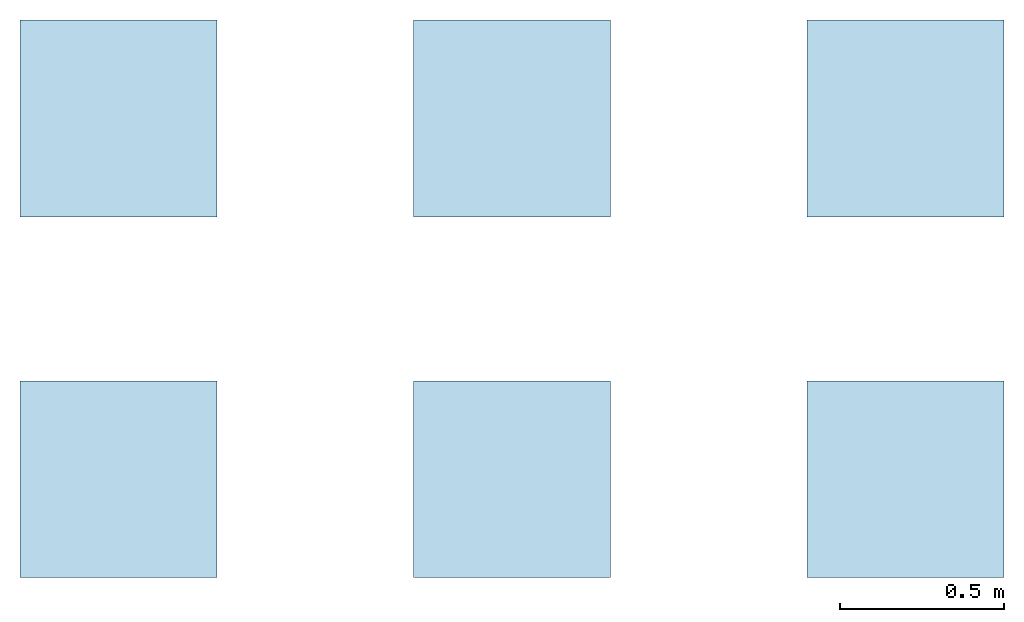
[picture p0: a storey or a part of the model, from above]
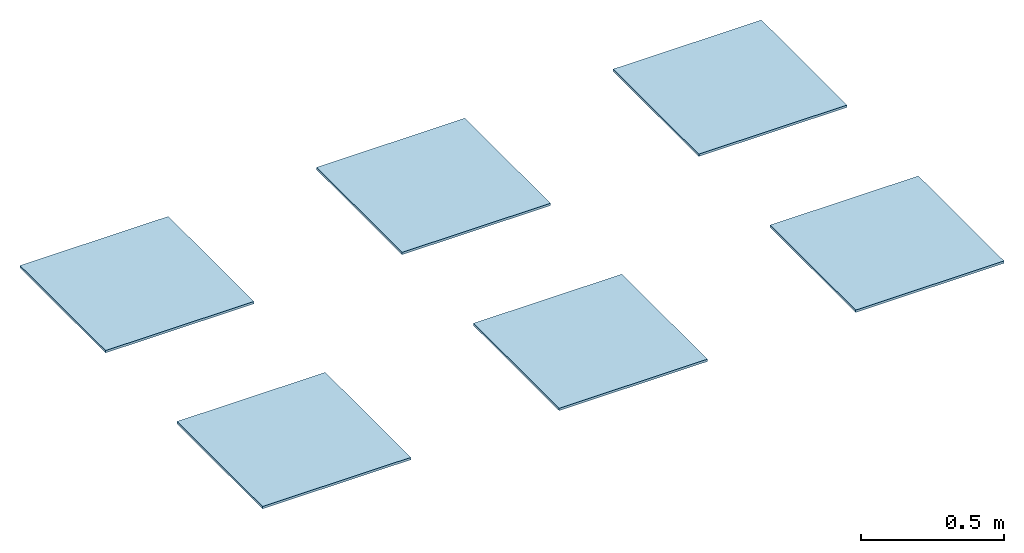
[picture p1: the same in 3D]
Properties of the parts of a building model (IFC2X3)

# File
Description: ViewDefinition [CoordinationView_V2.0]
File name: Número de proyecto
Time: 2017-10-19T11:49:41
Written by: The EXPRESS Data Manager Version 5.02.0100.07 : 28 Aug 2013
Made in: 20160225_1515(x64) - Exporter 17.0.416.0 - Alternate UI 17.12.14.0
Comment: STEP Physical File produced by: The EXPRESS Data Manager Version 5.02.0100.07 : 28 Aug 2013 * Module: EDMstepFileFactory/EDMstandAlone * Creation date: Thu Oct 19 11:49:41 2017 * Host: REVIT * Database: C:\Users\corte\AppData\Local\Temp\{BD6F1904-84B4-4D9F-9326-C3FF22E80287}\ifc * Database version: 5507 * Database creation date: Thu Oct 19 11:49:39 2017 * Schema: IFC2X3 * Model: DataRepository.ifc * Model creation date: Thu Oct 19 11:49:39 2017 * Header model: DataRepository.ifc_HeaderModel * Header model creation date: Thu Oct 19 11:49:39 2017 * EDMuser: sdai-user * EDMgroup: sdai-group * License ID and type: 5605 : Permanent license. Expiry date: * EDMstepFileFactory options: 020000

# IfcProject, Número de proyecto
LongName: Nombre de proyecto; Phase: Estado de proyecto

# IfcSite, Default
RefLatitude: 40, 25, 0, 86975; RefLongitude: -3, -42, -1, -243858; RefElevation: 0 m

# IfcBuilding
Pset_BuildingCommon - NumberOfStoreys: 2

# IfcBuildingStorey (2)
Name | LongName | Elevation (m)
LAVERTON FLOOR TILES | LAVERTON FLOOR TILES | 0
Nivel 2 | Nivel 2 | 3

# IfcSlab: Suelo:VIVES LAVERTON ARENA 60x60, Suelo:VIVES LAVERTON ARENA 60x60:189750
In: LAVERTON FLOOR TILES
PredefinedType: FLOOR; Material: VIVES LAVERTON ARENA 60x60 0.01 m
Pset_SlabCommon - Reference: VIVES LAVERTON ARENA 60x60; IsExternal: no; LoadBearing: yes; ThermalTransmittance: 150 kg/K/s3; PitchAngle: 0 deg
Pset_ManufacturerTypeInformation - Manufacturer: VIVES Azulejos y Gres S.A.

# IfcSlab: Suelo:VIVES LAVERTON BEIGE 60x60, Suelo:VIVES LAVERTON BEIGE 60x60:210667
In: LAVERTON FLOOR TILES
PredefinedType: FLOOR; Material: VIVES LAVERTON BEIGE 60x60 0.01 m
Pset_SlabCommon - IsExternal: no; LoadBearing: yes; PitchAngle: 0 deg; Reference: VIVES LAVERTON BEIGE 60x60; ThermalTransmittance: 150 kg/K/s3
Pset_ManufacturerTypeInformation - Manufacturer: VIVES Azulejos y Gres S.A.

# IfcSlab: Suelo:VIVES LAVERTON GRAFITO 60x60, Suelo:VIVES LAVERTON GRAFITO 60x60:210683
In: LAVERTON FLOOR TILES
PredefinedType: FLOOR; Material: VIVES LAVERTON GRAFITO 60x60 0.01 m
Pset_SlabCommon - IsExternal: no; LoadBearing: yes; PitchAngle: 0 deg; Reference: VIVES LAVERTON GRAFITO 60x60; ThermalTransmittance: 150 kg/K/s3
Pset_ManufacturerTypeInformation - Manufacturer: VIVES Azulejos y Gres S.A.

# IfcSlab: Suelo:VIVES LAVERTON GRIS 60x60, Suelo:VIVES LAVERTON GRIS 60x60:210675
In: LAVERTON FLOOR TILES
PredefinedType: FLOOR; Material: VIVES LAVERTON GRIS 60x60 0.01 m
Pset_SlabCommon - IsExternal: no; LoadBearing: yes; PitchAngle: 0 deg; Reference: VIVES LAVERTON GRIS 60x60; ThermalTransmittance: 150 kg/K/s3
Pset_ManufacturerTypeInformation - Manufacturer: VIVES Azulejos y Gres S.A.

# IfcSlab: Suelo:VIVES LAVERTON NATURAL 60x60, Suelo:VIVES LAVERTON NATURAL 60x60:210591
In: LAVERTON FLOOR TILES
PredefinedType: FLOOR; Material: VIVES LAVERTON NATURAL 60x60 0.01 m
Pset_SlabCommon - IsExternal: no; LoadBearing: yes; PitchAngle: 0 deg; Reference: VIVES LAVERTON NATURAL 60x60; ThermalTransmittance: 150 kg/K/s3
Pset_ManufacturerTypeInformation - Manufacturer: VIVES Azulejos y Gres S.A.

# IfcSlab: Suelo:VIVES LAVERTON NIEVE 60x60, Suelo:VIVES LAVERTON NIEVE 60x60:210450
In: LAVERTON FLOOR TILES
PredefinedType: FLOOR; Material: VIVES LAVERTON NIEVE 60x60 0.01 m
Pset_SlabCommon - IsExternal: no; LoadBearing: yes; PitchAngle: 0 deg; Reference: VIVES LAVERTON NIEVE 60x60; ThermalTransmittance: 150 kg/K/s3
Pset_ManufacturerTypeInformation - Manufacturer: VIVES Azulejos y Gres S.A.

# IfcWallStandardCase: Muro básico:VIVES LAVERTON ARENA 60x60, Muro básico:VIVES LAVERTON ARENA 60x60:204926
In: Nivel 2
Type - PredefinedType: STANDARD; Material: VIVES LAVERTON ARENA 60x60 0.01 m
Pset_WallCommon - Reference: VIVES LAVERTON ARENA 60x60; IsExternal: no; LoadBearing: no; ExtendToStructure: no; ThermalTransmittance: 150 kg/K/s3
Pset_ManufacturerTypeInformation - Manufacturer: VIVES Azulejos y Gres S.A.

# IfcWallStandardCase: Muro básico:VIVES LAVERTON BEIGE 60x60, Muro básico:VIVES LAVERTON BEIGE 60x60:211145
In: Nivel 2
Type - PredefinedType: STANDARD; Material: VIVES LAVERTON BEIGE 60x60 0.01 m
Pset_WallCommon - IsExternal: no; LoadBearing: no; ExtendToStructure: no; Reference: VIVES LAVERTON BEIGE 60x60; ThermalTransmittance: 150 kg/K/s3
Pset_ManufacturerTypeInformation - Manufacturer: VIVES Azulejos y Gres S.A.

# IfcWallStandardCase: Muro básico:VIVES LAVERTON GRAFITO 60x60, Muro básico:VIVES LAVERTON GRAFITO 60x60:211177
In: Nivel 2
Type - PredefinedType: STANDARD; Material: VIVES LAVERTON GRAFITO 60x60 0.01 m
Pset_WallCommon - IsExternal: no; LoadBearing: no; ExtendToStructure: no; Reference: VIVES LAVERTON GRAFITO 60x60; ThermalTransmittance: 150 kg/K/s3
Pset_ManufacturerTypeInformation - Manufacturer: VIVES Azulejos y Gres S.A.

# IfcWallStandardCase: Muro básico:VIVES LAVERTON GRIS 60x60, Muro básico:VIVES LAVERTON GRIS 60x60:211161
In: Nivel 2
Type - PredefinedType: STANDARD; Material: VIVES LAVERTON GRIS 60x60 0.01 m
Pset_WallCommon - IsExternal: no; LoadBearing: no; ExtendToStructure: no; Reference: VIVES LAVERTON GRIS 60x60; ThermalTransmittance: 150 kg/K/s3
Pset_ManufacturerTypeInformation - Manufacturer: VIVES Azulejos y Gres S.A.

# IfcWallStandardCase: Muro básico:VIVES LAVERTON NATURAL 60x60, Muro básico:VIVES LAVERTON NATURAL 60x60:211009
In: Nivel 2
Type - PredefinedType: STANDARD; Material: VIVES LAVERTON NATURAL 60x60 0.01 m
Pset_WallCommon - IsExternal: no; LoadBearing: no; ExtendToStructure: no; Reference: VIVES LAVERTON NATURAL 60x60; ThermalTransmittance: 150 kg/K/s3
Pset_ManufacturerTypeInformation - Manufacturer: VIVES Azulejos y Gres S.A.

# IfcWallStandardCase: Muro básico:VIVES LAVERTON NIEVE 60x60, Muro básico:VIVES LAVERTON NIEVE 60x60:210911
In: Nivel 2
Type - PredefinedType: STANDARD; Material: VIVES LAVERTON NIEVE 60x60 0.01 m
Pset_WallCommon - IsExternal: no; LoadBearing: no; ExtendToStructure: no; Reference: VIVES LAVERTON NIEVE 60x60; ThermalTransmittance: 150 kg/K/s3
Pset_ManufacturerTypeInformation - Manufacturer: VIVES Azulejos y Gres S.A.
